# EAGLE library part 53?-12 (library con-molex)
CONNECTOR wire to board 1.25 mm (.049 inch) pitch header

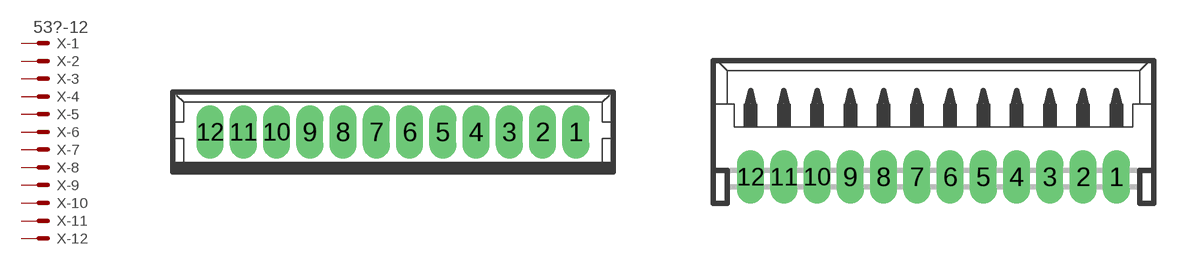
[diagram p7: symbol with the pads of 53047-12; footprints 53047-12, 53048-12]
Designator prefix X; gates -1=MV -2=M -3=M -4=M -5=M -6=M -7=M -8=M -9=M -10=M -11=M -12=M

## 53047-12  [53047-12]
1  -1:S  pas
2  -2:S  pas
3  -3:S  pas
4  -4:S  pas
5  -5:S  pas
6  -6:S  pas
7  -7:S  pas
8  -8:S  pas
9  -9:S  pas
10  -10:S  pas
11  -11:S  pas
12  -12:S  pas

## 53048-12  [53048-12]
Pads as for 53047-12

## 53261-12  [53261-12]
Pads as for 53047-12

## 53398-12  [53398-12]
Pads as for 53047-12

## Footprint 53047-12 (pad centres in mm)
CONNECTOR wire to board 1.25 mm (.049 inch) pitch header straight
drill 0.5 pad 0.698 long: 1 6.875,0; 2 5.625,0; 3 4.375,0; 4 3.125,0; 5 1.875,0; 6 0.625,0; 7 -0.625,0; 8 -1.875,0; 9 -3.125,0; 10 -4.375,0; 11 -5.625,0; 12 -6.875,0

## Footprint 53048-12 (pad centres in mm)
CONNECTOR wire to board 1.25 mm (.049 inch) pitch header right angle
drill 0.5 pad 0.698 long: 1 6.875,-1.25; 2 5.625,-1.25; 3 4.375,-1.25; 4 3.125,-1.25; 5 1.875,-1.25; 6 0.625,-1.25; 7 -0.625,-1.25; 8 -1.875,-1.25; 9 -3.125,-1.25; 10 -4.375,-1.25; 11 -5.625,-1.25; 12 -6.875,-1.25

## Footprint 53261-12 (pad centres in mm)
CONNECTOR wire to board 1.25 mm (.049 inch) pitch header SMT right angle
smd 0.8 x 2: 1 6.875,-2.5; 2 5.625,-2.5; 3 4.375,-2.5; 4 3.125,-2.5; 5 1.875,-2.5; 6 0.625,-2.5; 7 -0.625,-2.5; 8 -1.875,-2.5; 9 -3.125,-2.5; 10 -4.375,-2.5; 11 -5.625,-2.5; 12 -6.875,-2.5
smd 2.1 x 3: S1 9.375,0.625; S2 -9.375,0.625

## Footprint 53398-12 (pad centres in mm)
CONNECTOR wire to board 1.25 mm (.049 inch) pitch header SMT straight
smd 0.8 x 1.8: 1 6.875,-2.5; 2 5.625,-2.5; 3 4.375,-2.5; 4 3.125,-2.5; 5 1.875,-2.5; 6 0.625,-2.5; 7 -0.625,-2.5; 8 -1.875,-2.5; 9 -3.125,-2.5; 10 -4.375,-2.5; 11 -5.625,-2.5; 12 -6.875,-2.5
smd 2.1 x 3: S1 9.375,0.625; S2 -9.375,0.625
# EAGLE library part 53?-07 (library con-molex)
CONNECTOR wire to board 1.25 mm (.049 inch) pitch header

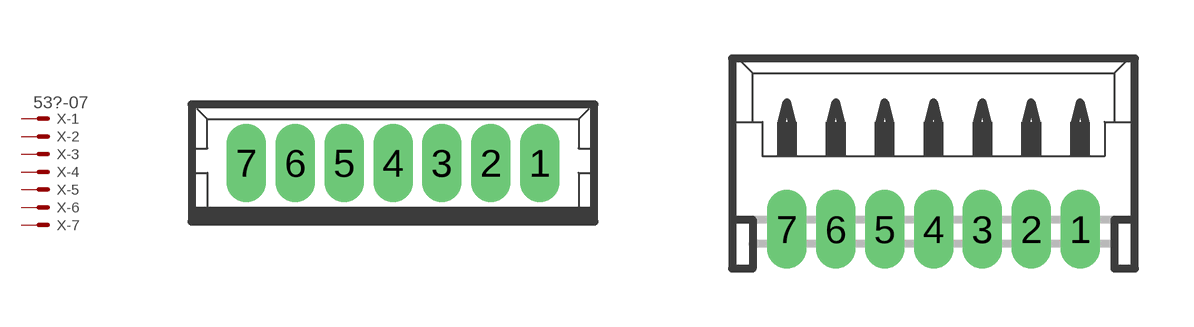
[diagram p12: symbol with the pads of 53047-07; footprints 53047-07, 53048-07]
Designator prefix X; gates -1=MV -2=M -3=M -4=M -5=M -6=M -7=M

## 53047-07  [53047-07]
1  -1:S  pas
2  -2:S  pas
3  -3:S  pas
4  -4:S  pas
5  -5:S  pas
6  -6:S  pas
7  -7:S  pas

## 53048-07  [53048-07]
Pads as for 53047-07

## 53261-07  [53261-07]
Pads as for 53047-07

## 53398-07  [53398-07]
Pads as for 53047-07

## Footprint 53047-07 (pad centres in mm)
CONNECTOR wire to board 1.25 mm (.049 inch) pitch header straight
drill 0.5 pad 0.698 long: 1 3.75,0; 2 2.5,0; 3 1.25,0; 4 0,0; 5 -1.25,0; 6 -2.5,0; 7 -3.75,0

## Footprint 53048-07 (pad centres in mm)
CONNECTOR wire to board 1.25 mm (.049 inch) pitch header right angle
drill 0.5 pad 0.698 long: 1 3.75,-1.25; 2 2.5,-1.25; 3 1.25,-1.25; 4 0,-1.25; 5 -1.25,-1.25; 6 -2.5,-1.25; 7 -3.75,-1.25

## Footprint 53261-07 (pad centres in mm)
CONNECTOR wire to board 1.25 mm (.049 inch) pitch header SMT right angle
smd 0.8 x 2: 1 3.75,-2.5; 2 2.5,-2.5; 3 1.25,-2.5; 4 0,-2.5; 5 -1.25,-2.5; 6 -2.5,-2.5; 7 -3.75,-2.5
smd 2.1 x 3: S1 6.25,0.625; S2 -6.25,0.625

## Footprint 53398-07 (pad centres in mm)
CONNECTOR wire to board 1.25 mm (.049 inch) pitch header SMT straight
smd 0.8 x 1.8: 1 3.75,-2.5; 2 2.5,-2.5; 3 1.25,-2.5; 4 0,-2.5; 5 -1.25,-2.5; 6 -2.5,-2.5; 7 -3.75,-2.5
smd 2.1 x 3: S1 6.25,0.625; S2 -6.25,0.625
